VERSION 5.7 ;
  NOWIREEXTENSIONATPIN ON ;
  DIVIDERCHAR "/" ;
  BUSBITCHARS "[]" ;
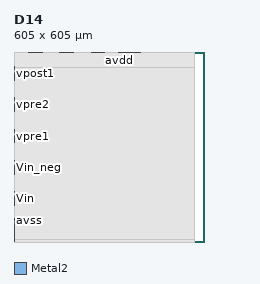
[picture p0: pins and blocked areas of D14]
MACRO D14
  CLASS BLOCK ;
  FOREIGN D14 ;
  ORIGIN 0.000 0.000 ;
  SIZE 605.000 BY 605.000 ;
  PIN Vin
    DIRECTION INOUT ;
    USE SIGNAL ;
    ANTENNAGATEAREA 5.000000 ;
    PORT
      LAYER Metal2 ;
        RECT 0.000 115.340 1.000 159.660 ;
    END
  END Vin
  PIN Vin_neg
    DIRECTION INOUT ;
    USE SIGNAL ;
    ANTENNAGATEAREA 5.000000 ;
    PORT
      LAYER Metal2 ;
        RECT 0.000 215.340 1.000 259.660 ;
    END
  END Vin_neg
  PIN avdd
    DIRECTION INOUT ;
    USE POWER ;
    PORT
      LAYER Metal2 ;
        RECT 331.360 604.000 340.860 605.000 ;
    END
  END avdd
  PIN avdd
    DIRECTION INOUT ;
    USE POWER ;
    PORT
      LAYER Metal2 ;
        RECT 343.760 604.000 354.010 605.000 ;
    END
  END avdd
  PIN avdd
    DIRECTION INOUT ;
    USE POWER ;
    PORT
      LAYER Metal2 ;
        RECT 355.610 604.000 365.860 605.000 ;
    END
  END avdd
  PIN avdd
    DIRECTION INOUT ;
    USE POWER ;
    PORT
      LAYER Metal2 ;
        RECT 369.140 604.000 379.390 605.000 ;
    END
  END avdd
  PIN avdd
    DIRECTION INOUT ;
    USE POWER ;
    PORT
      LAYER Metal2 ;
        RECT 380.990 604.000 391.240 605.000 ;
    END
  END avdd
  PIN avdd
    DIRECTION INOUT ;
    USE POWER ;
    PORT
      LAYER Metal2 ;
        RECT 394.140 604.000 403.640 605.000 ;
    END
  END avdd
  PIN avss
    DIRECTION INOUT ;
    USE GROUND ;
    PORT
      LAYER Metal2 ;
        RECT 0.000 1.360 1.000 10.860 ;
    END
  END avss
  PIN avss
    DIRECTION INOUT ;
    USE GROUND ;
    PORT
      LAYER Metal2 ;
        RECT 0.000 13.760 1.000 24.010 ;
    END
  END avss
  PIN avss
    DIRECTION INOUT ;
    USE GROUND ;
    PORT
      LAYER Metal2 ;
        RECT 0.000 25.610 1.000 35.860 ;
    END
  END avss
  PIN avss
    DIRECTION INOUT ;
    USE GROUND ;
    PORT
      LAYER Metal2 ;
        RECT 0.000 39.140 1.000 49.390 ;
    END
  END avss
  PIN avss
    DIRECTION INOUT ;
    USE GROUND ;
    PORT
      LAYER Metal2 ;
        RECT 0.000 50.990 1.000 61.240 ;
    END
  END avss
  PIN avss
    DIRECTION INOUT ;
    USE GROUND ;
    PORT
      LAYER Metal2 ;
        RECT 0.000 64.140 1.000 73.640 ;
    END
  END avss
  PIN vout_1
    DIRECTION INOUT ;
    USE SIGNAL ;
    ANTENNAGATEAREA 5.000000 ;
    ANTENNADIFFAREA 10.568000 ;
    PORT
      LAYER Metal2 ;
        RECT 145.340 604.000 189.660 605.000 ;
    END
  END vout_1
  PIN vout_2
    DIRECTION INOUT ;
    USE SIGNAL ;
    ANTENNAGATEAREA 5.000000 ;
    ANTENNADIFFAREA 10.568000 ;
    PORT
      LAYER Metal2 ;
        RECT 245.340 604.000 289.660 605.000 ;
    END
  END vout_2
  PIN vpost1
    DIRECTION INOUT ;
    USE SIGNAL ;
    ANTENNAGATEAREA 1.260000 ;
    ANTENNADIFFAREA 0.750000 ;
    PORT
      LAYER Metal2 ;
        RECT 0.000 515.340 1.000 559.660 ;
    END
  END vpost1
  PIN vpost2
    DIRECTION INOUT ;
    USE SIGNAL ;
    ANTENNAGATEAREA 1.260000 ;
    ANTENNADIFFAREA 0.750000 ;
    PORT
      LAYER Metal2 ;
        RECT 45.340 604.000 89.660 605.000 ;
    END
  END vpost2
  PIN vpre1
    DIRECTION INOUT ;
    USE SIGNAL ;
    ANTENNAGATEAREA 0.630000 ;
    ANTENNADIFFAREA 0.750000 ;
    PORT
      LAYER Metal2 ;
        RECT 0.000 315.340 1.000 359.660 ;
    END
  END vpre1
  PIN vpre2
    DIRECTION INOUT ;
    USE SIGNAL ;
    ANTENNAGATEAREA 0.630000 ;
    ANTENNADIFFAREA 0.750000 ;
    PORT
      LAYER Metal2 ;
        RECT 0.000 415.340 1.000 459.660 ;
    END
  END vpre2
  OBS
      LAYER Nwell ;
        RECT 182.000 88.300 524.810 414.235 ;
      LAYER Metal1 ;
        RECT 166.720 65.380 563.200 422.700 ;
      LAYER Metal2 ;
        RECT 0.140 603.700 45.040 604.000 ;
        RECT 89.960 603.700 145.040 604.000 ;
        RECT 189.960 603.700 245.040 604.000 ;
        RECT 289.960 603.700 331.060 604.000 ;
        RECT 341.160 603.700 343.460 604.000 ;
        RECT 354.310 603.700 355.310 604.000 ;
        RECT 366.160 603.700 368.840 604.000 ;
        RECT 379.690 603.700 380.690 604.000 ;
        RECT 391.540 603.700 393.840 604.000 ;
        RECT 403.940 603.700 572.180 604.000 ;
        RECT 0.140 559.960 572.180 603.700 ;
        RECT 1.300 515.040 572.180 559.960 ;
        RECT 0.140 459.960 572.180 515.040 ;
        RECT 1.300 415.040 572.180 459.960 ;
        RECT 0.140 359.960 572.180 415.040 ;
        RECT 1.300 315.040 572.180 359.960 ;
        RECT 0.140 259.960 572.180 315.040 ;
        RECT 1.300 215.040 572.180 259.960 ;
        RECT 0.140 159.960 572.180 215.040 ;
        RECT 1.300 115.040 572.180 159.960 ;
        RECT 0.140 73.940 572.180 115.040 ;
        RECT 1.300 63.840 572.180 73.940 ;
        RECT 0.140 61.540 572.180 63.840 ;
        RECT 1.300 50.690 572.180 61.540 ;
        RECT 0.140 49.690 572.180 50.690 ;
        RECT 1.300 38.840 572.180 49.690 ;
        RECT 0.140 36.160 572.180 38.840 ;
        RECT 1.300 25.310 572.180 36.160 ;
        RECT 0.140 24.310 572.180 25.310 ;
        RECT 1.300 13.460 572.180 24.310 ;
        RECT 0.140 11.160 572.180 13.460 ;
        RECT 1.300 1.360 572.180 11.160 ;
      LAYER Metal3 ;
        RECT 0.000 1.360 572.230 605.000 ;
      LAYER Metal4 ;
        RECT 0.140 0.000 573.700 603.680 ;
      LAYER Metal5 ;
        RECT 0.000 9.000 573.700 555.000 ;
  END
END D14
END LIBRARY

